VERSION 5.8 ;
BUSBITCHARS "[]" ;
DIVIDERCHAR "/" ;
CLEARANCEMEASURE EUCLIDEAN ;
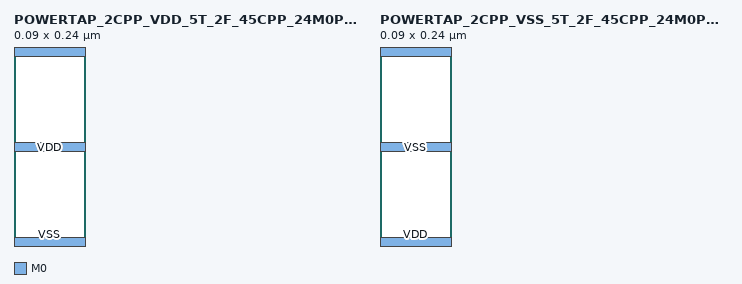
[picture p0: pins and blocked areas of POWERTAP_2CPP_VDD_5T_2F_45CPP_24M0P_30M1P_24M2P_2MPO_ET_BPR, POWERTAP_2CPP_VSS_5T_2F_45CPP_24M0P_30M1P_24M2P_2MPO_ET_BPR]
MACRO POWERTAP_2CPP_VDD_5T_2F_45CPP_24M0P_30M1P_24M2P_2MPO_ET_BPR
  CLASS CORE ;
  ORIGIN 0 0 ;
  FOREIGN POWERTAP_2CPP_VDD_5T_2F_45CPP_24M0P_30M1P_24M2P_2MPO_ET_BPR ;
  SIZE 0.090 BY 0.24 ;
  SYMMETRY X Y ;
  SITE coresite ;
  PIN VSS
    DIRECTION INOUT ;
    USE GROUND ;
    SHAPE ABUTMENT ;
    PORT
      LAYER M0 ;
        RECT 0.000 -0.006 0.090 0.006 ;
        RECT 0.000 0.234 0.090 0.246 ;
    END
  END VSS
  PIN VDD
    DIRECTION INOUT ;
    USE POWER ;
    SHAPE ABUTMENT ;
    PORT
      LAYER M0 ;
        RECT 0.000 0.114 0.090 0.126 ;
    END
  END VDD
END POWERTAP_2CPP_VDD_5T_2F_45CPP_24M0P_30M1P_24M2P_2MPO_ET_BPR

MACRO POWERTAP_2CPP_VSS_5T_2F_45CPP_24M0P_30M1P_24M2P_2MPO_ET_BPR
  CLASS CORE ;
  ORIGIN 0 0 ;
  FOREIGN POWERTAP_2CPP_VSS_5T_2F_45CPP_24M0P_30M1P_24M2P_2MPO_ET_BPR ;
  SIZE 0.090 BY 0.24 ;
  SYMMETRY X Y ;
  SITE coresite ;
  PIN VDD
    DIRECTION INOUT ;
    USE POWER ;
    SHAPE ABUTMENT ;
    PORT
      LAYER M0 ;
        RECT 0.000 -0.006 0.090 0.006 ;
        RECT 0.000 0.234 0.090 0.246 ;
    END
  END VDD
  PIN VSS
    DIRECTION INOUT ;
    USE GROUND ;
    SHAPE ABUTMENT ;
    PORT
      LAYER M0 ;
        RECT 0.000 0.114 0.090 0.126 ;
    END
  END VSS
END POWERTAP_2CPP_VSS_5T_2F_45CPP_24M0P_30M1P_24M2P_2MPO_ET_BPR
